VERSION 5.7 ;
  NOWIREEXTENSIONATPIN ON ;
  DIVIDERCHAR "/" ;
  BUSBITCHARS "[]" ;
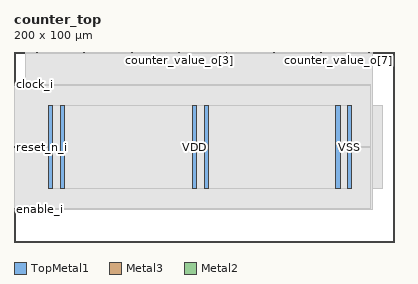
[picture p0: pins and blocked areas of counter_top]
MACRO counter_top
  CLASS BLOCK ;
  FOREIGN counter_top ;
  ORIGIN 0.000 0.000 ;
  SIZE 200.000 BY 100.000 ;
  PIN VDD
    DIRECTION INOUT ;
    USE POWER ;
    PORT
      LAYER TopMetal1 ;
        RECT 18.260 28.340 20.460 71.620 ;
    END
    PORT
      LAYER TopMetal1 ;
        RECT 93.860 28.340 96.060 71.620 ;
    END
    PORT
      LAYER TopMetal1 ;
        RECT 169.460 28.340 171.660 71.620 ;
    END
  END VDD
  PIN VSS
    DIRECTION INOUT ;
    USE GROUND ;
    PORT
      LAYER TopMetal1 ;
        RECT 24.460 27.930 26.660 72.030 ;
    END
    PORT
      LAYER TopMetal1 ;
        RECT 100.060 27.930 102.260 72.030 ;
    END
    PORT
      LAYER TopMetal1 ;
        RECT 175.660 27.930 177.860 72.030 ;
    END
  END VSS
  PIN clock_i
    DIRECTION INPUT ;
    USE SIGNAL ;
    ANTENNAGATEAREA 9.261000 ;
    PORT
      LAYER Metal3 ;
        RECT 0.000 82.540 0.400 82.940 ;
    END
  END clock_i
  PIN counter_value_o[0]
    DIRECTION OUTPUT ;
    USE SIGNAL ;
    ANTENNADIFFAREA 1.297350 ;
    PORT
      LAYER Metal2 ;
        RECT 11.800 99.600 12.200 100.000 ;
    END
  END counter_value_o[0]
  PIN counter_value_o[1]
    DIRECTION OUTPUT ;
    USE SIGNAL ;
    ANTENNADIFFAREA 1.297350 ;
    PORT
      LAYER Metal2 ;
        RECT 36.760 99.600 37.160 100.000 ;
    END
  END counter_value_o[1]
  PIN counter_value_o[2]
    DIRECTION OUTPUT ;
    USE SIGNAL ;
    ANTENNADIFFAREA 1.297350 ;
    PORT
      LAYER Metal2 ;
        RECT 61.720 99.600 62.120 100.000 ;
    END
  END counter_value_o[2]
  PIN counter_value_o[3]
    DIRECTION OUTPUT ;
    USE SIGNAL ;
    ANTENNADIFFAREA 1.297350 ;
    PORT
      LAYER Metal2 ;
        RECT 86.680 99.600 87.080 100.000 ;
    END
  END counter_value_o[3]
  PIN counter_value_o[4]
    DIRECTION OUTPUT ;
    USE SIGNAL ;
    ANTENNADIFFAREA 1.297350 ;
    PORT
      LAYER Metal2 ;
        RECT 111.640 99.600 112.040 100.000 ;
    END
  END counter_value_o[4]
  PIN counter_value_o[5]
    DIRECTION OUTPUT ;
    USE SIGNAL ;
    ANTENNADIFFAREA 1.297350 ;
    PORT
      LAYER Metal2 ;
        RECT 136.600 99.600 137.000 100.000 ;
    END
  END counter_value_o[5]
  PIN counter_value_o[6]
    DIRECTION OUTPUT ;
    USE SIGNAL ;
    ANTENNADIFFAREA 1.297350 ;
    PORT
      LAYER Metal2 ;
        RECT 161.560 99.600 161.960 100.000 ;
    END
  END counter_value_o[6]
  PIN counter_value_o[7]
    DIRECTION OUTPUT ;
    USE SIGNAL ;
    ANTENNADIFFAREA 1.297350 ;
    PORT
      LAYER Metal2 ;
        RECT 186.520 99.600 186.920 100.000 ;
    END
  END counter_value_o[7]
  PIN enable_i
    DIRECTION INPUT ;
    USE SIGNAL ;
    ANTENNAGATEAREA 1.154250 ;
    PORT
      LAYER Metal3 ;
        RECT 0.000 17.020 0.400 17.420 ;
    END
  END enable_i
  PIN reset_n_i
    DIRECTION INPUT ;
    USE SIGNAL ;
    ANTENNAGATEAREA 1.154250 ;
    PORT
      LAYER Metal3 ;
        RECT 0.000 49.780 0.400 50.180 ;
    END
  END reset_n_i
  OBS
      LAYER GatPoly ;
        RECT 5.760 28.410 193.920 71.550 ;
      LAYER Metal1 ;
        RECT 5.760 28.340 193.920 71.620 ;
      LAYER Metal2 ;
        RECT 6.135 99.390 11.590 99.600 ;
        RECT 12.410 99.390 36.550 99.600 ;
        RECT 37.370 99.390 61.510 99.600 ;
        RECT 62.330 99.390 86.470 99.600 ;
        RECT 87.290 99.390 111.430 99.600 ;
        RECT 112.250 99.390 136.390 99.600 ;
        RECT 137.210 99.390 161.350 99.600 ;
        RECT 162.170 99.390 186.310 99.600 ;
        RECT 187.130 99.390 188.905 99.600 ;
        RECT 6.135 17.075 188.905 99.390 ;
      LAYER Metal3 ;
        RECT 0.610 82.330 187.825 82.840 ;
        RECT 0.400 50.390 187.825 82.330 ;
        RECT 0.610 49.570 187.825 50.390 ;
        RECT 0.400 17.630 187.825 49.570 ;
        RECT 0.610 17.120 187.825 17.630 ;
      LAYER Metal4 ;
        RECT 18.440 28.415 177.680 71.545 ;
      LAYER Metal5 ;
        RECT 18.395 28.250 177.725 71.710 ;
  END
END counter_top
END LIBRARY

